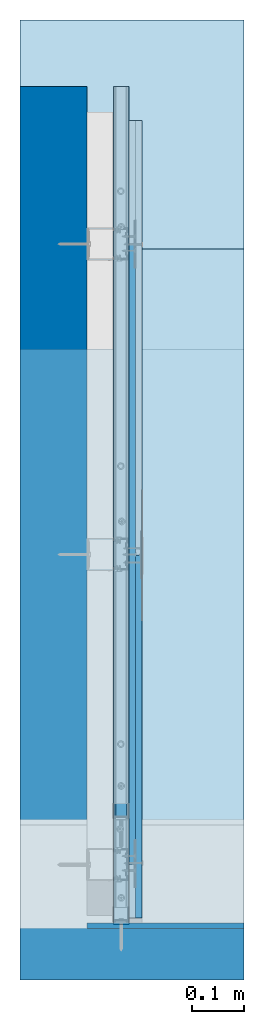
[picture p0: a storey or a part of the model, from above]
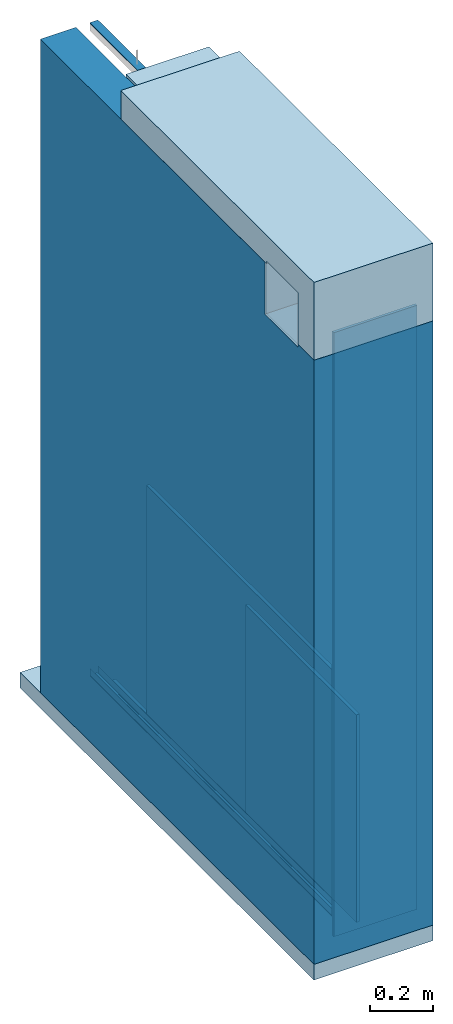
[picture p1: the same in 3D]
Properties of the parts of a building model (IFC2X3)

# File
Description: ViewDefinition [CoordinationView_V2.0]
File name: kolizja nr 1.ifc
Time: 2025-11-19T12:30:15
Written by: IFC-manager for SketchUp (5.5.4)
Made in: SketchUp 2026 (26.0.429)

# IfcSite (2)
Description: Description of Default Site; RefElevation: 254 mm

# IfcBuilding (2)
Description: Description of Default Building; ElevationOfRefHeight: 0 mm; ElevationOfTerrain: 0 mm

# IfcBuildingStorey (2)
In: Default Building
Description: Description of Default Building Storey; Elevation: 57.6156 mm
Parametry kolizji SG - Elementkolizyjnykonstrukcyjnyinstalacyjny: Belka żelbetowa; ElementsystemuSaintGobain: Okładzina ścienna 3.21.10; Izolacyjnoscakustyczna: zgodna z izolacyjnością akustyczną przegrody; Klasaodpornosciogniowej: zgodna z klasą odporności przegrody; LODlevelofDevelopment: 400; Producent: SAINT-GOBAIN; Typkolizji: twarda
Name | Nrdetalu | Opis | Sposobwykonania | Warianty
Default Building Storey | 5.05.223 | Detal przejścia belki żelbetowej zlokalizowanej w narożu przez okładzinę ścienną wykonaną w systemie RIGIPS | W przypadku wystÄ…pienia belki Å¼elbetowej w naroÅ¼u okÅ‚adziny Å›ciennej w systemie RIGIPS naleÅ¼y profil poziomy UD 30 zamocowaÄ‡ do dolnej powierzchni belki, uprzednio podklejajÄ…c go taÅ›mÄ… uszczelniajÄ…cÄ… piankowÄ… RIGIPS. Profile pionowe CD 60 powinny byÄ‡ dociÄ™te do wysokoÅ›ci odpowiadajÄ…cej odlegÅ‚oÅ›ci od stropu dolnego do powierzchni dolnej belki, pomniejszonej o 10 mm. W przypadku mocowania profilu UD 30 do bocznej powierzchni Å›ciany konstrukcyjnej naleÅ¼y go dociÄ…Ä‡ na wysokoÅ›Ä‡ rÃ³wnÄ… odlegÅ‚oÅ›ci od stropu dolnego do powierzchni dolnej belki, pomniejszonÄ… o 10 mm, a nastÄ™pnie zastosowaÄ‡ podklejonÄ… taÅ›mÄ™ uszczelniajÄ…cÄ… piankowÄ… RIGIPS i dopiero wtedy zamocowaÄ‡ profil do konstrukcji. Pierwszy profil pionowy CD 60 naleÅ¼y umieÅ›ciÄ‡ w odlegÅ‚oÅ›ci maksymalnej 150mm od powierzchni Å›ciany bocznej. Kolejny profil pionowy naleÅ¼y zastosowaÄ‡ w odlegÅ‚oÅ›ci nie wiÄ™kszej niÅ¼ 600 mm i odlegÅ‚oÅ›ci od powierzchni bocznej belki nie wiÄ™kszej niÅ¼ 150mm . Na bocznej powierzchni belki naleÅ¼y zastosowaÄ‡ profil obwodowy UD 30 w celu usztywnienia konstrukcji, bez potrzeby montowania pÅ‚yt g-k do niego. Na powierzchniach belki oraz na wszystkich elementach konstrukcyjnych stykajÄ…cych siÄ™ z okÅ‚adzinÄ… Å›ciennÄ… naleÅ¼y wykonaÄ‡ poÅ‚Ä…czenie Å›lizgowe zgodnie z zasadami systemu RIGIPS. Do przygotowanej konstrukcji naleÅ¼y zamontowaÄ‡ pÅ‚yty gipsowo-kartonowe, odpowiednio dociÄ™te w miejscu styku z belkÄ…, przy czym elementy docinane nie mogÄ… byÄ‡ krÃ³tsze niÅ¼ 40 cm. Spoiny w rejonie styku z belkÄ… Å¼elbetowÄ… naleÅ¼y wypeÅ‚niÄ‡ gipsowÄ… masÄ… konstrukcyjnÄ… RIGIPS, co zapewni trwaÅ‚e i szczelne wykoÅ„czenie okÅ‚adziny. | W narożniku ściany i sufitu
Default Building Storey | 5.05.224 | Detal przejścia belki żelbetowej zlokalizowanej pod stropem przez okładzinę ścienną wykonaną w systemie RIGIPS | W przypadku wystÄ…pienia belki Å¼elbetowej pod stropem w rozwiÄ…zaniu okÅ‚adziny Å›ciennej w systemie RIGIPS naleÅ¼y profil poziomy UD 30 zamocowaÄ‡ do dolnej powierzchni belki, uprzednio podklejajÄ…c go taÅ›mÄ… uszczelniajÄ…cÄ… piankowÄ… RIGIPS. Profile pionowe CD 60 powinny byÄ‡ dociÄ™te do wysokoÅ›ci odpowiadajÄ…cej odlegÅ‚oÅ›ci od stropu dolnego do powierzchni dolnej belki, pomniejszonej o 10 mm. Profile pionowe CD 60 naleÅ¼y montowaÄ‡ zachowujÄ…c maksymalny rozstaw rÃ³wny 600 mm. Na bocznych powierzchniach moÅ¼na zastosowaÄ‡ profil obwodowy UD 30 w celu usztywnienia konstrukcji, bez potrzeby montowania pÅ‚yt gipsowo-kartonowych do niego. Na powierzchniach belki oraz na wszystkich elementach konstrukcyjnych stykajÄ…cych siÄ™ z okÅ‚adzinÄ… Å›ciennÄ… naleÅ¼y wykonaÄ‡ poÅ‚Ä…czenie Å›lizgowe zgodnie z zasadami systemu RIGIPS. Do przygotowanej konstrukcji naleÅ¼y zamontowaÄ‡ pÅ‚yty gipsowo-kartonowe, odpowiednio dociÄ™te w miejscu styku z belkÄ…, przy czym elementy docinane nie mogÄ… byÄ‡ krÃ³tsze niÅ¼ 40 cm. Spoiny w rejonie styku z belkÄ… Å¼elbetowÄ… naleÅ¼y wypeÅ‚niÄ‡ gipsowÄ… masÄ… konstrukcyjnÄ… RIGIPS, co zapewni trwaÅ‚e i szczelne wykoÅ„czenie okÅ‚adziny. | Przy suficie

# IfcSlab: Beton (2)
In: Default Building Storey
Type - PredefinedType: FLOOR
Material: Concrete_02_1K
Qto_SlabBaseQuantities - NetVolume: 0.048222 m3; Depth: 59.9996 mm; NetArea: 0.803705 m2

# IfcSlab: Strop
In: Default Building Storey
Type - PredefinedType: FLOOR
Material: Concrete_02_1K
Qto_SlabBaseQuantities - NetVolume: 0.0626827 m3; Depth: 300 mm; NetArea: 0.208942 m2

# IfcSlab: Strop#1, Strop
In: Default Building Storey
Type - PredefinedType: FLOOR
Material: M04_Stone_Frost
Qto_SlabBaseQuantities - NetVolume: 0.00337239 m3; Depth: 10 mm; NetArea: 0.337239 m2

# IfcSlab: Strop#2, Strop
In: Default Building Storey
Type - PredefinedType: FLOOR
Material: M04_Stone_Frost
Qto_SlabBaseQuantities - NetVolume: 0.00394809 m3; Depth: 200 mm; NetArea: 0.0197404 m2

# IfcSlab: Strop#3, Strop
In: Default Building Storey
Type - PredefinedType: FLOOR
Material: Concrete_02_1K
Qto_SlabBaseQuantities - NetVolume: 0.0629297 m3; Depth: 300 mm; NetArea: 0.209766 m2

# IfcWall: Belka żelbetowa (2)
In: Default Building Storey
Material: M05_Graphite_Haze
Qto_WallBaseQuantities - NetVolume: 0.0173213 m3

# IfcWall: Kołek rozporowy min. fi 6#11 (5)
In: Default Building Storey
Type - Description: Description of Object
Material: Default

# IfcWall: Kołek rozporowy min. fi 6#12 (26)
In: Default Building Storey
Type - Description: Description of Object
Material: Default

# IfcWall: Kołek rozporowy min. fi 6#14 (5)
In: Default Building Storey
Type - Description: Description of Object
Material: Default

# IfcWall: Kołek rozporowy min. fi 6#15 (26)
In: Default Building Storey
Type - Description: Description of Object
Material: Default

# IfcWall: Kołek rozporowy min. fi 6#26 (4)
In: Default Building Storey
Type - Description: Description of Object
Material: Default

# IfcWall: Kołek rozporowy min. fi 6#30 (4)
In: Default Building Storey
Type - Description: Description of Object
Material: Default

# IfcWall: Kołek rozporowy min. fi 6#35 (18)
In: Default Building Storey
Type - Description: Description of Object
Material: Default

# IfcWall: Kołek rozporowy min. fi 6#36 (18)
In: Default Building Storey
Type - Description: Description of Object
Material: Default

# IfcWall: Masa szpachlowa konstrukcyjna RIGIPS (2)
In: Default Building Storey
Type - Description: Description of Object
Material: Undefined5
Qto_WallBaseQuantities - NetVolume: 0.0000600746 m3; Width: 3.20005 mm; Length: 91 mm; NetSideArea: 0.018773 m2

# IfcWall: Masa szpachlowa konstrukcyjna RIGIPS#1, Masa szpachlowa konstrukcyjna RIGIPS
In: Default Building Storey
Type - Description: Description of Object
Material: Undefined5
Qto_WallBaseQuantities - NetVolume: 0.000579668 m3

# IfcWall: Masa szpachlowa konstrukcyjna RIGIPS#2 (4)
In: Default Building Storey
Type - Description: Description of Object
Material: Undefined5
Qto_WallBaseQuantities - NetVolume: 0.0000938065 m3; Width: 3.20005 mm; Length: 91 mm; NetSideArea: 0.029314 m2

# IfcWall: Masa szpachlowa konstrukcyjna RIGIPS#3, Masa szpachlowa konstrukcyjna RIGIPS
In: Default Building Storey
Type - Description: Description of Object
Material: Undefined5
Qto_WallBaseQuantities - NetVolume: 0.000385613 m3

# IfcWall: Masa szpachlowa konstrukcyjna RIGIPS#4, Masa szpachlowa konstrukcyjna RIGIPS
In: Default Building Storey
Type - Description: Description of Object
Material: Undefined5
Qto_WallBaseQuantities - NetVolume: 0.000628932 m3

# IfcWall: Masa szpachlowa konstrukcyjna RIGIPS#5, Masa szpachlowa konstrukcyjna RIGIPS
In: Default Building Storey
Type - Description: Description of Object
Material: Undefined5
Qto_WallBaseQuantities - NetVolume: 0.000385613 m3

# IfcWall: Masa szpachlowa wykończeniowa RIGIPS (2)
In: Default Building Storey
Type - Description: Description of Object
Material: Undefined2
Qto_WallBaseQuantities - NetVolume: 0.0000477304 m3; Width: 0.959873 mm; Length: 250 mm; NetSideArea: 0.0497257 m2

# IfcWall: Profil
In: Default Building Storey
Material: M06_Steel_Smoke
Qto_WallBaseQuantities - NetVolume: 0.00259807 m3

# IfcWall: Profil RIGIPS CD 60 GypSerra®/Ultrastil®#2 (2)
In: Default Building Storey
Type - Description: Description of Object
Material: Default

# IfcWall: Profil RIGIPS CD 60 GypSerra®/Ultrastil®#4 (4)
In: Default Building Storey
Type - Description: Description of Object
Material: Default

# IfcWall: Profil RIGIPS UD 30 GypSerra®/Ultrastil® (2)
In: Default Building Storey
Type - Description: Description of Object
Material: Undefined9
Qto_WallBaseQuantities - NetVolume: 0.0000727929 m3

# IfcWall: Profil RIGIPS UD 30 GypSerra®/Ultrastil®#1, Profil RIGIPS UD 30 GypSerra®/Ultrastil®
In: Default Building Storey
Type - Description: Description of Object
Material: Undefined9
Qto_WallBaseQuantities - NetVolume: 0.000106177 m3

# IfcWall: Profil RIGIPS UD 30 GypSerra®/Ultrastil®#2, Profil RIGIPS UD 30 GypSerra®/Ultrastil®
In: Default Building Storey
Type - Description: Description of Object
Material: Undefined9
Qto_WallBaseQuantities - NetVolume: 0.00000793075 m3

# IfcWall: Profil RIGIPS UD 30 GypSerra®/Ultrastil®#3, Profil RIGIPS UD 30 GypSerra®/Ultrastil®
In: Default Building Storey
Type - Description: Description of Object
Material: Undefined9
Qto_WallBaseQuantities - NetVolume: 0.0000104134 m3

# IfcWall: Profil RIGIPS UD 30 GypSerra®/Ultrastil®#4, Profil RIGIPS UD 30 GypSerra®/Ultrastil®
In: Default Building Storey
Type - Description: Description of Object
Material: Undefined9
Qto_WallBaseQuantities - NetVolume: 0.0000636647 m3

# IfcWall: Profil RIGIPS UD 30 GypSerra®/Ultrastil®#5 (2)
In: Default Building Storey
Type - Description: Description of Object
Material: Undefined9
Qto_WallBaseQuantities - NetVolume: 0.00000917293 m3

# IfcWall: Profil RIGIPS UD 30 GypSerra®/Ultrastil®#6, Profil RIGIPS UD 30 GypSerra®/Ultrastil®
In: Default Building Storey
Type - Description: Description of Object
Material: Undefined9
Qto_WallBaseQuantities - NetVolume: 0.00000917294 m3

# IfcWall: Profil RIGIPS UD 30 GypSerra®/Ultrastil®#7, Profil RIGIPS UD 30 GypSerra®/Ultrastil®
In: Default Building Storey
Type - Description: Description of Object
Material: Undefined9
Qto_WallBaseQuantities - NetVolume: 0.0000103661 m3

# IfcWall: Profil RIGIPS UD 30 GypSerra®/Ultrastil®#8, Profil RIGIPS UD 30 GypSerra®/Ultrastil®
In: Default Building Storey
Type - Description: Description of Object
Material: Undefined9
Qto_WallBaseQuantities - NetVolume: 0.000113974 m3

# IfcWall: Profil#1, Profil
In: Default Building Storey
Material: M06_Steel_Smoke

# IfcWall: Płyta gipsowo-kartonowa RIGIPS PRO (4PRO™)#1 (2)
In: Default Building Storey
Type - Description: Description of Object
Material: Undefined7
Qto_WallBaseQuantities - NetVolume: 0.00112391 m3; Width: 12.5 mm; Length: 103.369 mm; NetSideArea: 0.0899131 m2

# IfcWall: Płyta gipsowo-kartonowa RIGIPS PRO (4PRO™)#2 (2)
In: Default Building Storey
Type - Description: Description of Object
Material: Undefined7
Qto_WallBaseQuantities - NetVolume: 0.0134204 m3; Width: 12.5 mm; Length: 1199.84 mm; NetSideArea: 1.07363 m2

# IfcWall: Płyta gipsowo-kartonowa RIGIPS PRO (4PRO™)#3 (2)
In: Default Building Storey
Type - Description: Description of Object
Material: Undefined7
Qto_WallBaseQuantities - NetVolume: 0.00264762 m3; Width: 12.5 mm; Length: 238.802 mm; NetSideArea: 0.21181 m2

# IfcWall: Płyta gipsowo-kartonowa RIGIPS PRO (4PRO™)#4 (2)
In: Default Building Storey
Type - Description: Description of Object
Material: Undefined7
Qto_WallBaseQuantities - NetVolume: 0.0069702 m3; Width: 12.5 mm; Length: 700.477 mm; NetSideArea: 0.557616 m2

# IfcWall: Płyta gipsowo-kartonowa RIGIPS PRO (4PRO™)#5 (2)
In: Default Building Storey
Type - Description: Description of Object
Material: Undefined7
Qto_WallBaseQuantities - NetVolume: 0.00837078 m3; Width: 12.5 mm; Length: 840.534 mm; NetSideArea: 0.669662 m2

# IfcWall: Taśma spoinowa RIGIPS (2)
In: Default Building Storey
Type - Description: Description of Object
Material: Undefined8
Qto_WallBaseQuantities - NetVolume: 0.0000165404 m3; Width: 0.500202 mm; Length: 50 mm; NetSideArea: 0.0330675 m2

# IfcWall: Taśma uszczelniająca piankowa RIGIPS szer.30mm#9 (18)
In: Default Building Storey
Type - Description: Description of Object
Material: Default

# IfcWall: Taśma uszczelniająca piankowa RIGIPS#1, Taśma uszczelniająca piankowa RIGIPS
In: Default Building Storey
Type - Description: Description of Object
Material: Undefined13
Qto_WallBaseQuantities - NetVolume: 0.00022365 m3

# IfcWall: Taśma uszczelniająca piankowa RIGIPS#2, Taśma uszczelniająca piankowa RIGIPS
In: Default Building Storey
Type - Description: Description of Object
Material: Undefined13
Qto_WallBaseQuantities - NetVolume: 0.000208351 m3

# IfcWall: Taśma uszczelniająca piankowa RIGIPS#3 (4)
In: Default Building Storey
Type - Description: Description of Object
Material: Undefined13
Qto_WallBaseQuantities - NetVolume: 0.000145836 m3

# IfcWall: Taśma uszczelniająca piankowa RIGIPS#4, Taśma uszczelniająca piankowa RIGIPS
In: Default Building Storey
Type - Description: Description of Object
Material: Undefined13
Qto_WallBaseQuantities - NetVolume: 0.0000182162 m3

# IfcWall: Taśma uszczelniająca piankowa RIGIPS#5, Taśma uszczelniająca piankowa RIGIPS
In: Default Building Storey
Type - Description: Description of Object
Material: Undefined13
Qto_WallBaseQuantities - NetVolume: 0.0000180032 m3

# IfcWall: Taśma uszczelniająca piankowa RIGIPS#6, Taśma uszczelniająca piankowa RIGIPS
In: Default Building Storey
Type - Description: Description of Object
Material: Undefined13
Qto_WallBaseQuantities - NetVolume: 0.0000180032 m3

# IfcWall: Taśma uszczelniająca piankowa RIGIPS#7, Taśma uszczelniająca piankowa RIGIPS
In: Default Building Storey
Type - Description: Description of Object
Material: Undefined13
Qto_WallBaseQuantities - NetVolume: 0.0000198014 m3

# IfcWall: Taśma uszczelniająca piankowa RIGIPS#8, Taśma uszczelniająca piankowa RIGIPS
In: Default Building Storey
Type - Description: Description of Object
Material: Undefined13
Qto_WallBaseQuantities - NetVolume: 0.0000180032 m3

# IfcWall: Uchwyt Rigips ES do profili CD60 (18)
In: Default Building Storey
Type - Description: Description of Object
Name | Material
6 x Uchwyt Rigips ES do profili CD60 | Default
12 x Uchwyt Rigips ES do profili CD60 | Undefined3

# IfcWall: Wkręt 3,9x11mm pchełka#15 (18)
In: Default Building Storey
Type - Description: Description of Object
Name | Material
6 x Wkręt RIGIPS "pchełka" 3,9x11mm | Default
12 x Wkręt RIGIPS "pchełka" 3,9x11mm | Undefined4

# IfcWall: Wkręt 3,9x11mm pchełka#3 (18)
In: Default Building Storey
Type - Description: Description of Object
Name | Material
6 x Wkręt RIGIPS "pchełka" 3,9x11mm | Default
12 x Wkręt RIGIPS "pchełka" 3,9x11mm | Undefined4

# IfcWall: Wkręt 3,9x11mm pchełka#37 (18)
In: Default Building Storey
Type - Description: Description of Object
Material: Undefined4

# IfcWall: Wkręt 3,9x11mm pchełka#9 (18)
In: Default Building Storey
Type - Description: Description of Object
Name | Material
6 x Wkręt RIGIPS "pchełka" 3,9x11mm | Default
12 x Wkręt RIGIPS "pchełka" 3,9x11mm | Undefined4

# IfcWall: Wkręt RIGIPS TN 25#16 (8)
In: Default Building Storey
Type - Description: Description of Object
Material: Default

# IfcWall: Wkręt RIGIPS TN 25#17 (8)
In: Default Building Storey
Type - Description: Description of Object
Material: Default

# IfcWall: Wkręt RIGIPS TN 25#24 (4)
In: Default Building Storey
Type - Description: Description of Object
Material: Default

# IfcWall: Wkręt RIGIPS TN 35#29 (2)
In: Default Building Storey
Type - Description: Description of Object
Material: Default

# IfcWall: Wkręt RIGIPS TN 35#30 (2)
In: Default Building Storey
Type - Description: Description of Object
Material: Default

# IfcWall: Wkręt RIGIPS TN 35#31 (2)
In: Default Building Storey
Type - Description: Description of Object
Material: Default

# IfcWall: Wkręt RIGIPS TN 35#32 (2)
In: Default Building Storey
Type - Description: Description of Object
Material: Default

# IfcWall: Wkręt RIGIPS TN 35#33 (2)
In: Default Building Storey
Type - Description: Description of Object
Material: Default

# IfcWall: Wkręt RIGIPS TN 35#43 (2)
In: Default Building Storey
Type - Description: Description of Object
Material: Default

# IfcWall: Wkręt RIGIPS TN 35#44 (2)
In: Default Building Storey
Type - Description: Description of Object
Material: Default

# IfcWall: Wkręt RIGIPS TN 35#45 (2)
In: Default Building Storey
Type - Description: Description of Object
Material: Default

# IfcWall: Wkręt RIGIPS TN 35#46 (2)
In: Default Building Storey
Type - Description: Description of Object
Material: Default

# IfcWall: Wkręt RIGIPS TN 35#47 (2)
In: Default Building Storey
Type - Description: Description of Object
Material: Default

# IfcWall: Wkręt RIGIPS TN 35#48 (2)
In: Default Building Storey
Type - Description: Description of Object
Material: Default

# IfcWall: Wkręt RIGIPS TN 35#49 (2)
In: Default Building Storey
Type - Description: Description of Object
Material: Default

# IfcWall: Wypełnienie z wełny mineralnej szklanej ISOVER#1 (2)
In: Default Building Storey
Type - Description: Description of Object
Material: Undefined
Qto_WallBaseQuantities - NetVolume: 0.00260013 m3; Width: 49.9999 mm; Length: 57.7 mm; NetSideArea: 0.0520027 m2

# IfcWall: Wypełnienie z wełny mineralnej szklanej ISOVER#10, Wypełnienie z wełny mineralnej szklanej ISOVER
In: Default Building Storey
Type - Description: Description of Object
Material: Default

# IfcWall: Wypełnienie z wełny mineralnej szklanej ISOVER#11, Wypełnienie z wełny mineralnej szklanej ISOVER
In: Default Building Storey
Type - Description: Description of Object
Material: Undefined
Qto_WallBaseQuantities - NetVolume: 0.00306687 m3; Width: 49.9999 mm; Length: 67.8781 mm; NetSideArea: 0.0613376 m2

# IfcWall: Wypełnienie z wełny mineralnej szklanej ISOVER#12, Wypełnienie z wełny mineralnej szklanej ISOVER
In: Default Building Storey
Type - Description: Description of Object
Material: Default

# IfcWall: Wypełnienie z wełny mineralnej szklanej ISOVER#13, Wypełnienie z wełny mineralnej szklanej ISOVER
In: Default Building Storey
Type - Description: Description of Object
Material: Undefined
Qto_WallBaseQuantities - NetVolume: 0.00305782 m3; Width: 49.9999 mm; Length: 67.8781 mm; NetSideArea: 0.0611564 m2

# IfcWall: Wypełnienie z wełny mineralnej szklanej ISOVER#14, Wypełnienie z wełny mineralnej szklanej ISOVER
In: Default Building Storey
Type - Description: Description of Object
Material: Undefined
Qto_WallBaseQuantities - NetVolume: 0.00306687 m3; Width: 49.9999 mm; Length: 67.8781 mm; NetSideArea: 0.0613376 m2

# IfcWall: Wypełnienie z wełny mineralnej szklanej ISOVER#15, Wypełnienie z wełny mineralnej szklanej ISOVER
In: Default Building Storey
Type - Description: Description of Object
Material: Default

# IfcWall: Wypełnienie z wełny mineralnej szklanej ISOVER#16, Wypełnienie z wełny mineralnej szklanej ISOVER
In: Default Building Storey
Type - Description: Description of Object
Material: Default

# IfcWall: Wypełnienie z wełny mineralnej szklanej ISOVER#17, Wypełnienie z wełny mineralnej szklanej ISOVER
In: Default Building Storey
Type - Description: Description of Object
Material: Default

# IfcWall: Wypełnienie z wełny mineralnej szklanej ISOVER#18, Wypełnienie z wełny mineralnej szklanej ISOVER
In: Default Building Storey
Type - Description: Description of Object
Material: Default

# IfcWall: Wypełnienie z wełny mineralnej szklanej ISOVER#2, Wypełnienie z wełny mineralnej szklanej ISOVER
In: Default Building Storey
Type - Description: Description of Object
Material: Default

# IfcWall: Wypełnienie z wełny mineralnej szklanej ISOVER#3, Wypełnienie z wełny mineralnej szklanej ISOVER
In: Default Building Storey
Type - Description: Description of Object
Material: Default

# IfcWall: Wypełnienie z wełny mineralnej szklanej ISOVER#4 (2)
In: Default Building Storey
Type - Description: Description of Object
Material: Undefined
Qto_WallBaseQuantities - NetVolume: 0.00260013 m3; Width: 49.9999 mm; Length: 57.7 mm; NetSideArea: 0.0520027 m2

# IfcWall: Wypełnienie z wełny mineralnej szklanej ISOVER#5 (8)
In: Default Building Storey
Type - Description: Description of Object
Material: Undefined
Qto_WallBaseQuantities - NetVolume: 0.0242438 m3; Width: 49.9999 mm; Length: 538 mm; NetSideArea: 0.484878 m2

# IfcWall: Wypełnienie z wełny mineralnej szklanej ISOVER#6 (2)
In: Default Building Storey
Type - Description: Description of Object
Material: Undefined
Qto_WallBaseQuantities - NetVolume: 0.010099 m3; Width: 50 mm; Length: 224.108 mm; NetSideArea: 0.20198 m2

# IfcWall: Wypełnienie z wełny mineralnej szklanej ISOVER#7, Wypełnienie z wełny mineralnej szklanej ISOVER
In: Default Building Storey
Type - Description: Description of Object
Material: Undefined
Qto_WallBaseQuantities - NetVolume: 0.00305878 m3; Width: 49.9999 mm; Length: 67.8781 mm; NetSideArea: 0.0611757 m2

# IfcWall: Wypełnienie z wełny mineralnej szklanej ISOVER#8, Wypełnienie z wełny mineralnej szklanej ISOVER
In: Default Building Storey
Type - Description: Description of Object
Material: Undefined
Qto_WallBaseQuantities - NetVolume: 0.00173595 m3; Width: 49.9999 mm; Length: 67.8781 mm; NetSideArea: 0.034719 m2

# IfcWall: Wypełnienie z wełny mineralnej szklanej ISOVER#9, Wypełnienie z wełny mineralnej szklanej ISOVER
In: Default Building Storey
Type - Description: Description of Object
Material: Undefined
Qto_WallBaseQuantities - NetVolume: 0.00241473 m3; Width: 49.9999 mm; Length: 67.8781 mm; NetSideArea: 0.0482946 m2

# IfcWall: Ściana#1 (2)
In: Default Building Storey
Material: M04_Stone_Frost
Qto_WallBaseQuantities - NetVolume: 0.00705387 m3

# IfcWall: Ściana#2, Ściana
In: Default Building Storey
Material: M03_Pewter_Shine
Qto_WallBaseQuantities - NetVolume: 0.62826 m3; Width: 433 mm; Length: 2518.01 mm; NetSideArea: 1.45095 m2

# IfcWall: Ściana#3, Ściana
In: Default Building Storey
Material: M03_Pewter_Shine
Qto_WallBaseQuantities - NetVolume: 0.627753 m3; Width: 433 mm; Length: 2518.01 mm; NetSideArea: 1.44978 m2
